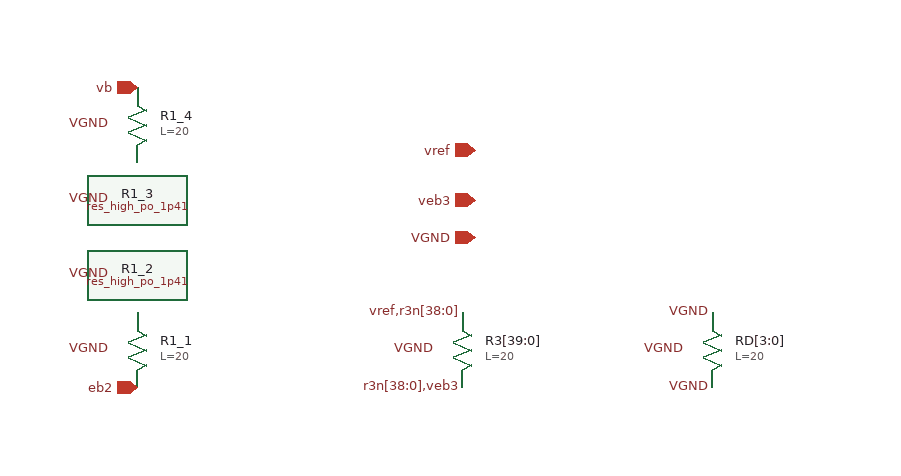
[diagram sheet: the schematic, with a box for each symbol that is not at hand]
v {xschem version=3.4.8RC file_version=1.3}
G {}
K {}
V {}
S {}
F {}
E {}
C {sky130_fd_pr/res_high_po_1p41.sym} 0 -30 0 0 {name=R1_1
L=20
model=res_high_po_1p41
spiceprefix=X
mult=1}
C {sky130_fd_pr/res_high_po_1p41.sym} 0 -90 0 0 {name=R1_2
L=20
model=res_high_po_1p41
spiceprefix=X
mult=1}
C {sky130_fd_pr/res_high_po_1p41.sym} 0 -150 0 0 {name=R1_3
L=20
model=res_high_po_1p41
spiceprefix=X
mult=1}
C {sky130_fd_pr/res_high_po_1p41.sym} 0 -210 0 0 {name=R1_4
L=20
model=res_high_po_1p41
spiceprefix=X
mult=1}
C {sky130_fd_pr/res_high_po_1p41.sym} 260 -30 0 0 {name=R3[39:0]
L=20
model=res_high_po_1p41
spiceprefix=X
mult=1}
C {sky130_fd_pr/res_high_po_1p41.sym} 460 -30 0 0 {name=RD[3:0]
L=20
model=res_high_po_1p41
spiceprefix=X
mult=1}
C {iopin.sym} 0 -240 0 0 {name=p1 lab=vb}
C {iopin.sym} 0 0 0 0 {name=p2 lab=eb2}
C {lab_pin.sym} 260 -60 0 0 {name=p3 sig_type=std_logic lab=vref,r3n[38:0]}
C {lab_pin.sym} 260 0 0 0 {name=p4 sig_type=std_logic lab=r3n[38:0],veb3}
C {iopin.sym} 270 -190 0 0 {name=p5 lab=vref}
C {iopin.sym} 270 -150 0 0 {name=p6 lab=veb3}
C {lab_pin.sym} 240 -30 0 0 {name=p7 sig_type=std_logic lab=VGND}
C {lab_pin.sym} -20 -210 0 0 {name=p8 sig_type=std_logic lab=VGND}
C {lab_pin.sym} -20 -150 0 0 {name=p9 sig_type=std_logic lab=VGND}
C {lab_pin.sym} -20 -90 0 0 {name=p10 sig_type=std_logic lab=VGND}
C {lab_pin.sym} -20 -30 0 0 {name=p11 sig_type=std_logic lab=VGND}
C {lab_pin.sym} 460 -60 0 0 {name=p12 sig_type=std_logic lab=VGND}
C {lab_pin.sym} 440 -30 0 0 {name=p13 sig_type=std_logic lab=VGND}
C {lab_pin.sym} 460 0 0 0 {name=p14 sig_type=std_logic lab=VGND}
C {iopin.sym} 270 -120 0 0 {name=p15 lab=VGND}
